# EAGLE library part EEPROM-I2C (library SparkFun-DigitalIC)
I2C EEPROM chips, 24LC256 (and others)

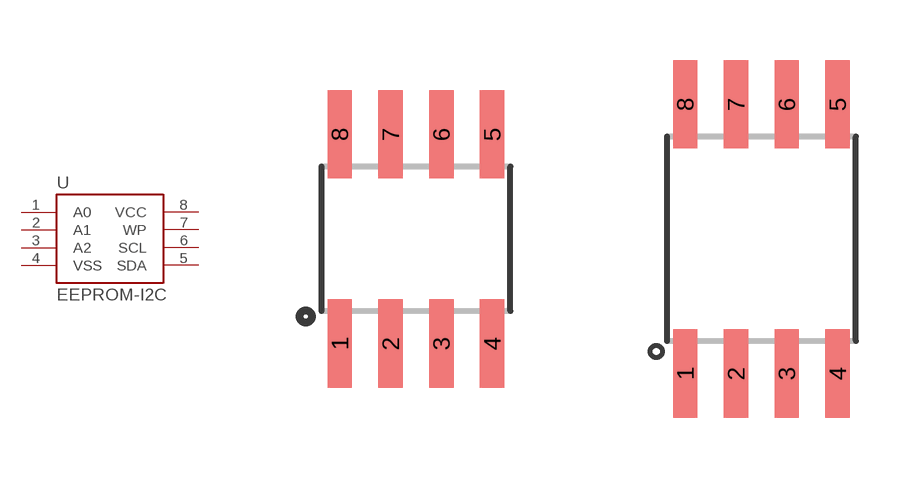
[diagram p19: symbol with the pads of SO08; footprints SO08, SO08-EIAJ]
Designator prefix U

## EEPROM-I2CSMD  [SO08]
1  A0
2  A1
3  A2
4  VSS  pwr
5  SDA
6  SCL
7  WP
8  VCC  pwr

## EEPROM-I2CEIAJ  [SO08-EIAJ]
Pads as for SO08

## Footprint SO08 (pad centres in mm)
Small Outline Package Fits JEDEC packages (narrow SOIC-8)
smd 0.61 x 2.21: 1 -1.905,-2.616; 2 -0.635,-2.616; 3 0.635,-2.616; 4 1.905,-2.616; 5 1.905,2.616; 6 0.635,2.616; 7 -0.635,2.616; 8 -1.905,2.616

## Footprint SO08-EIAJ (pad centres in mm)
Fits EIAJ packages (wide version of the SOIC-8).
smd 0.61 x 2.21: 1 -1.905,-3.378; 2 -0.635,-3.378; 3 0.635,-3.378; 4 1.905,-3.378; 5 1.905,3.353; 6 0.635,3.353; 7 -0.635,3.353; 8 -1.905,3.353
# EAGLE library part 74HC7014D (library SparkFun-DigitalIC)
The 74HC7014 is a hex buffer with precision Schmitt-trigger inputs. The precisely defined trigger levels are lying in a window between (0.55 x VCC) and (0.65 x VCC). It makes the circuit suitable to operate in a highly noisy environment. Input shorts are allowed to -1.5 V and +16 V without disturbing other channels. Inputs include clamp diodes that enable the use of current limiting resistors to interface inputs to voltages in excess of VCC. Schmitt trigger inputs transform slowly changing input signals into sharply defined jitter-free output signals.

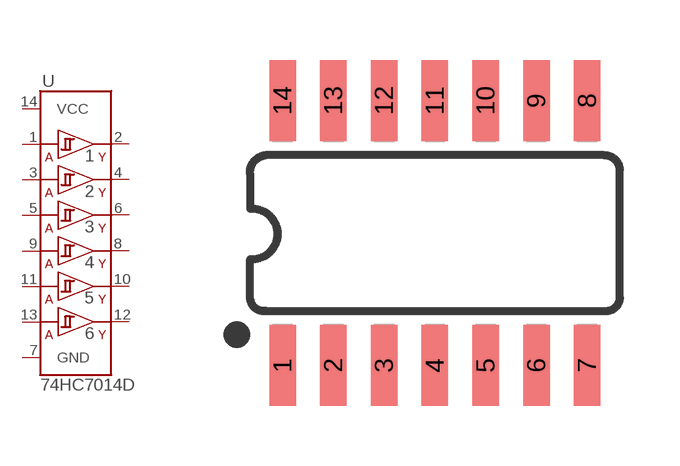
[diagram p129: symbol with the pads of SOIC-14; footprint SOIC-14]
Designator prefix U

## 74HC7014D (PROD_ID: IC-12527)  [SOIC-14]
1  1A  in
2  1Y  out
3  2A  in
4  2Y  out
5  3A  in
6  3Y  out
7  GND  pwr
8  4Y  out
9  4A  in
10  5Y  out
11  5A  in
12  6Y  out
13  6A  in
14  VCC  pwr

## Footprint SOIC-14 (pad centres in mm)
smd 0.66 x 2.032: 1 -4.445,-3.315; 2 -3.175,-3.315; 3 -1.905,-3.315; 4 -0.635,-3.315; 5 0.635,-3.315; 6 1.905,-3.315; 7 3.175,-3.315; 8 3.175,3.315; 9 1.905,3.315; 10 0.635,3.315; 11 -0.635,3.315; 12 -1.905,3.315; 13 -3.175,3.315; 14 -4.445,3.315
